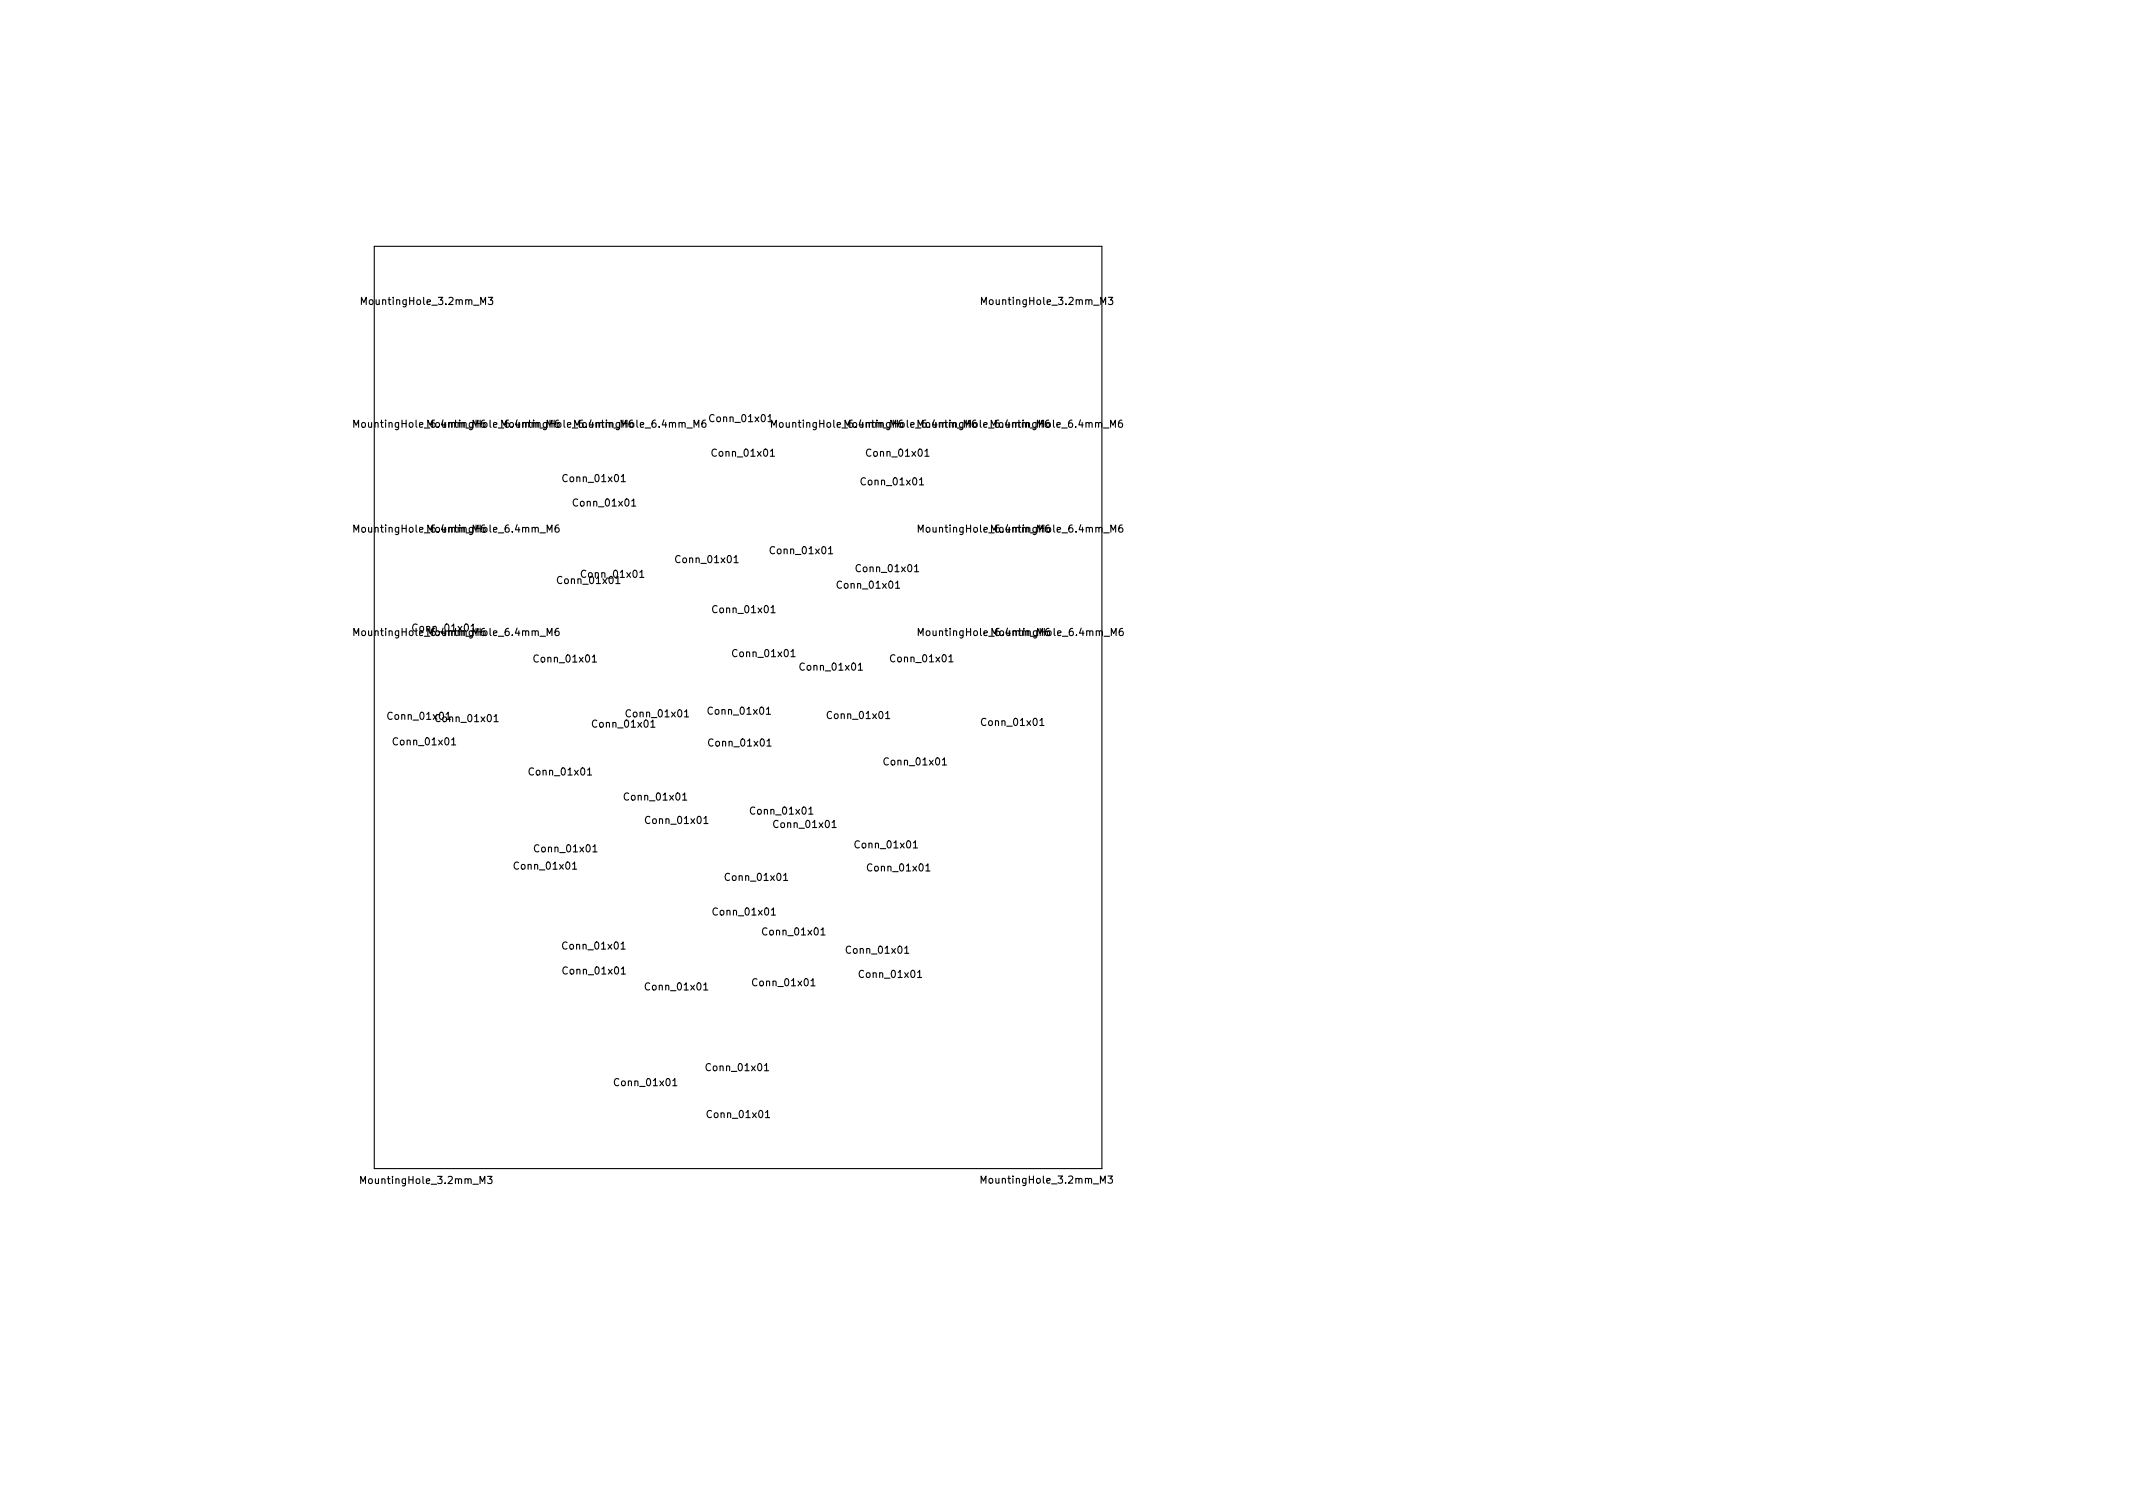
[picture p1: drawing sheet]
<svg xmlns="http://www.w3.org/2000/svg" width="297mm" height="210mm" viewBox="0 0 297 210" stroke-linecap="round" stroke-linejoin="round" font-family="sans-serif">
<defs><g id="words">
<g font-size="1.4">
<text x="50.9" y="42.4">MountingHole_3.2mm_M3</text>
<text x="137.2" y="42.4">MountingHole_3.2mm_M3</text>
<text x="49.8" y="59.5">MountingHole_6.4mm_M6</text>
<text x="60.1" y="59.5">MountingHole_6.4mm_M6</text>
<text x="70.4" y="59.5">MountingHole_6.4mm_M6</text>
<text x="80.6" y="59.5">MountingHole_6.4mm_M6</text>
<text x="99.1" y="58.8">Conn_01x01</text>
<text x="108" y="59.5">MountingHole_6.4mm_M6</text>
<text x="118.2" y="59.5">MountingHole_6.4mm_M6</text>
<text x="128.4" y="59.5">MountingHole_6.4mm_M6</text>
<text x="138.6" y="59.5">MountingHole_6.4mm_M6</text>
<text x="99.4" y="63.6">Conn_01x01</text>
<text x="120.9" y="63.6">Conn_01x01</text>
<text x="78.6" y="67.1">Conn_01x01</text>
<text x="80.1" y="70.5">Conn_01x01</text>
<text x="120.2" y="67.6">Conn_01x01</text>
<text x="49.8" y="74.1">MountingHole_6.4mm_M6</text>
<text x="60.1" y="74.1">MountingHole_6.4mm_M6</text>
<text x="107.5" y="77.2">Conn_01x01</text>
<text x="128.4" y="74.1">MountingHole_6.4mm_M6</text>
<text x="138.6" y="74.1">MountingHole_6.4mm_M6</text>
<text x="77.9" y="81.3">Conn_01x01</text>
<text x="81.2" y="80.4">Conn_01x01</text>
<text x="94.3" y="78.4">Conn_01x01</text>
<text x="116.8" y="82">Conn_01x01</text>
<text x="119.5" y="79.7">Conn_01x01</text>
<text x="49.8" y="88.5">MountingHole_6.4mm_M6</text>
<text x="57.7" y="87.9">Conn_01x01</text>
<text x="60.1" y="88.5">MountingHole_6.4mm_M6</text>
<text x="99.5" y="85.4">Conn_01x01</text>
<text x="128.4" y="88.5">MountingHole_6.4mm_M6</text>
<text x="138.7" y="88.5">MountingHole_6.4mm_M6</text>
<text x="74.6" y="92.2">Conn_01x01</text>
<text x="102.3" y="91.5">Conn_01x01</text>
<text x="111.6" y="93.4">Conn_01x01</text>
<text x="124.3" y="92.2">Conn_01x01</text>
<text x="54.2" y="100.2">Conn_01x01</text>
<text x="60.9" y="100.5">Conn_01x01</text>
<text x="82.7" y="101.3">Conn_01x01</text>
<text x="87.4" y="99.9">Conn_01x01</text>
<text x="98.8" y="99.5">Conn_01x01</text>
<text x="115.4" y="100.1">Conn_01x01</text>
<text x="136.9" y="101.1">Conn_01x01</text>
<text x="55" y="103.8">Conn_01x01</text>
<text x="73.9" y="108">Conn_01x01</text>
<text x="98.9" y="103.9">Conn_01x01</text>
<text x="123.3" y="106.6">Conn_01x01</text>
<text x="87.2" y="111.5">Conn_01x01</text>
<text x="104.7" y="113.4">Conn_01x01</text>
<text x="74.7" y="118.7">Conn_01x01</text>
<text x="90.1" y="114.7">Conn_01x01</text>
<text x="108" y="115.3">Conn_01x01</text>
<text x="119.3" y="118.1">Conn_01x01</text>
<text x="71.8" y="121.1">Conn_01x01</text>
<text x="101.2" y="122.6">Conn_01x01</text>
<text x="121" y="121.3">Conn_01x01</text>
<text x="99.5" y="127.5">Conn_01x01</text>
<text x="106.4" y="130.2">Conn_01x01</text>
<text x="78.6" y="132.2">Conn_01x01</text>
<text x="78.6" y="135.7">Conn_01x01</text>
<text x="90.1" y="137.9">Conn_01x01</text>
<text x="105" y="137.3">Conn_01x01</text>
<text x="118.1" y="132.8">Conn_01x01</text>
<text x="119.9" y="136.2">Conn_01x01</text>
<text x="98.6" y="149.1">Conn_01x01</text>
<text x="85.8" y="151.2">Conn_01x01</text>
<text x="98.7" y="155.7">Conn_01x01</text>
<text x="50.8" y="164.8">MountingHole_3.2mm_M3</text>
<text x="137.2" y="164.8">MountingHole_3.2mm_M3</text>
</g>
</g></defs>
<g fill="none" stroke="#000" stroke-width=".15">
<path d="M52.1 34.3h101.4v128.4h-101.4zM49.3 59.5v-1l.3 .7 .3-.7v1M50.3 42.4v-1l.4 .7 .3-.7v1M68 41.4h.6l-.3 .4 .3 .1v.4l-.2 .1-.4-.1M98.2 58.5h-.3a.67 .67 0 0 0 0 1l.4-.1v-.3l-.2-.2h-.3l-.1 .2M107 58.7h.5M107.4 59.5v-1l.4 .7 .3-.7v1M136.7 42.4v-1l.3 .7 .3-.7v1M154.3 41.4h.7l-.4 .4 .3 .1v.4l-.1 .1-.5-.1M156.2 58.5h-.3a.67 .67 0 0 0 0 1l.4-.1v-.3l-.2-.2h-.2l-.1 .2M49.3 74.1v-1l.3 .7 .3-.7v1M77.8 73.1h-.3a.67 .67 0 0 0 0 1l.3-.1 .1-.3-.2-.2h-.2l-.2 .2"/>
<path d="M86.5 67.1h.6M88 70.5h.5M102.2 78.4h.6M107.3 63.5h.6M115.4 77.1h.6M127.4 79.6h.5M127.9 74.1v-1l.3 .7 .3-.7v1M128 67.5h.6M128.8 63.5h.6M156.3 73.1h-.3a.67 .67 0 0 0 0 1l.3-.1 .1-.3-.2-.2h-.2l-.2 .2M49.3 88.5v-1l.3 .7 .3-.7v1M77.8 87.5h-.3a.67 .67 0 0 0 0 1l.3-.1 .1-.3-.2-.2h-.2l-.2 .2"/>
<path d="M82.5 92.2h.6M85.8 81.3h.5M89.1 80.4h.6M95.3 99.8h.6M106.7 99.5h.6M107.4 85.3h.5M110.2 91.4h.5M119.5 93.3h.6M124.7 81.9h.6M127.9 88.5v-1l.3 .7 .3-.7v1M132.1 92.2h.6M156.3 87.5h-.3a.67 .67 0 0 0 0 1l.4-.1v-.3l-.2-.2h-.2l-.1 .2"/>
<path d="M62.9 103.7h.6M68.8 100.5h.6M81.8 107.9h.6M82.6 118.6h.5M90.6 101.3h.6M95.1 111.4h.5M98 114.7h.6M106.8 103.9h.6M112.6 113.4h.6M115.9 115.2h.5M123.3 100.1h.6M127.2 118.1h.6"/>
<path d="M131.2 106.5h.6M144.8 101h.6M79.7 121h.6M86.5 132.2h.6M86.5 135.6h.6M98 137.9h.6M107.4 127.4h.6M109.1 122.6h.6M112.9 137.3h.6M114.3 130.2h.6M126 132.7h.6M127.8 136.1h.6"/>
<path d="M128.9 121.3h.6M93.7 151.2h.6M106.5 149.1h.5M106.6 155.6h.6M50.2 164.8v-1l.4 .7 .3-.7v1M67.9 163.8h.6l-.3 .4 .3 .1v.4l-.2 .1-.4-.1M136.6 164.8v-1l.4 .7 .3-.7v1M154.3 163.8h.6l-.3 .3 .3 .1v.5l-.2 .1-.4-.1"/>
</g>
<use href="#words"/>
</svg>
